VERSION 5.7 ;
  NOWIREEXTENSIONATPIN ON ;
  DIVIDERCHAR "/" ;
  BUSBITCHARS "[]" ;
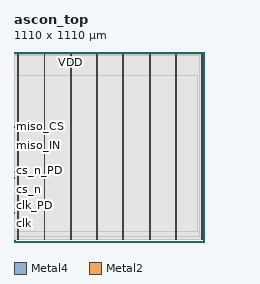
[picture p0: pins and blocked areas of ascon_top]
MACRO ascon_top
  CLASS BLOCK ;
  FOREIGN ascon_top ;
  ORIGIN 0.000 0.000 ;
  SIZE 1110.000 BY 1110.000 ;
  PIN VDD
    DIRECTION INOUT ;
    USE POWER ;
    PORT
      LAYER Metal4 ;
        RECT 22.240 15.380 23.840 1093.980 ;
    END
    PORT
      LAYER Metal4 ;
        RECT 175.840 15.380 177.440 1093.980 ;
    END
    PORT
      LAYER Metal4 ;
        RECT 329.440 15.380 331.040 1093.980 ;
    END
    PORT
      LAYER Metal4 ;
        RECT 483.040 15.380 484.640 1093.980 ;
    END
    PORT
      LAYER Metal4 ;
        RECT 636.640 15.380 638.240 1093.980 ;
    END
    PORT
      LAYER Metal4 ;
        RECT 790.240 15.380 791.840 1093.980 ;
    END
    PORT
      LAYER Metal4 ;
        RECT 943.840 15.380 945.440 1093.980 ;
    END
    PORT
      LAYER Metal4 ;
        RECT 1097.440 15.380 1099.040 1093.980 ;
    END
  END VDD
  PIN VSS
    DIRECTION INOUT ;
    USE GROUND ;
    PORT
      LAYER Metal4 ;
        RECT 25.540 15.380 27.140 1093.980 ;
    END
    PORT
      LAYER Metal4 ;
        RECT 179.140 15.380 180.740 1093.980 ;
    END
    PORT
      LAYER Metal4 ;
        RECT 332.740 15.380 334.340 1093.980 ;
    END
    PORT
      LAYER Metal4 ;
        RECT 486.340 15.380 487.940 1093.980 ;
    END
    PORT
      LAYER Metal4 ;
        RECT 639.940 15.380 641.540 1093.980 ;
    END
    PORT
      LAYER Metal4 ;
        RECT 793.540 15.380 795.140 1093.980 ;
    END
    PORT
      LAYER Metal4 ;
        RECT 947.140 15.380 948.740 1093.980 ;
    END
    PORT
      LAYER Metal4 ;
        RECT 1100.740 15.380 1102.340 1093.980 ;
    END
  END VSS
  PIN clk
    DIRECTION INPUT ;
    USE SIGNAL ;
    ANTENNAGATEAREA 4.738000 ;
    PORT
      LAYER Metal2 ;
        RECT 0.000 108.760 1.000 109.140 ;
    END
  END clk
  PIN clk_PD
    DIRECTION OUTPUT ;
    USE SIGNAL ;
    ANTENNADIFFAREA 0.360800 ;
    PORT
      LAYER Metal2 ;
        RECT 0.000 169.290 1.000 169.670 ;
    END
  END clk_PD
  PIN clk_PU
    DIRECTION OUTPUT ;
    USE SIGNAL ;
    ANTENNADIFFAREA 0.360800 ;
    PORT
      LAYER Metal2 ;
        RECT 0.000 173.655 1.000 174.035 ;
    END
  END clk_PU
  PIN cs_n
    DIRECTION INPUT ;
    USE SIGNAL ;
    ANTENNAGATEAREA 0.726000 ;
    PORT
      LAYER Metal2 ;
        RECT 0.000 308.760 1.000 309.140 ;
    END
  END cs_n
  PIN cs_n_PD
    DIRECTION OUTPUT ;
    USE SIGNAL ;
    ANTENNADIFFAREA 0.360800 ;
    PORT
      LAYER Metal2 ;
        RECT 0.000 369.290 1.000 369.670 ;
    END
  END cs_n_PD
  PIN cs_n_PU
    DIRECTION OUTPUT ;
    USE SIGNAL ;
    ANTENNADIFFAREA 0.360800 ;
    PORT
      LAYER Metal2 ;
        RECT 0.000 373.655 1.000 374.035 ;
    END
  END cs_n_PU
  PIN miso_CS
    DIRECTION OUTPUT ;
    USE SIGNAL ;
    ANTENNADIFFAREA 0.360800 ;
    PORT
      LAYER Metal2 ;
        RECT 0.000 676.260 1.000 676.640 ;
    END
  END miso_CS
  PIN miso_IE
    DIRECTION OUTPUT ;
    USE SIGNAL ;
    ANTENNADIFFAREA 0.360800 ;
    PORT
      LAYER Metal2 ;
        RECT 0.000 668.235 1.000 668.615 ;
    END
  END miso_IE
  PIN miso_IN
    DIRECTION INPUT ;
    USE SIGNAL ;
    ANTENNAGATEAREA 0.498500 ;
    PORT
      LAYER Metal2 ;
        RECT 0.000 608.760 1.000 609.140 ;
    END
  END miso_IN
  PIN miso_OE
    DIRECTION OUTPUT ;
    USE SIGNAL ;
    ANTENNADIFFAREA 0.536800 ;
    PORT
      LAYER Metal2 ;
        RECT 0.000 609.490 1.000 609.870 ;
    END
  END miso_OE
  PIN miso_OUT
    DIRECTION OUTPUT ;
    USE SIGNAL ;
    ANTENNADIFFAREA 1.986000 ;
    PORT
      LAYER Metal2 ;
        RECT 0.000 610.220 1.000 610.600 ;
    END
  END miso_OUT
  PIN miso_PD
    DIRECTION OUTPUT ;
    USE SIGNAL ;
    ANTENNADIFFAREA 0.360800 ;
    PORT
      LAYER Metal2 ;
        RECT 0.000 669.290 1.000 669.670 ;
    END
  END miso_PD
  PIN miso_PDRV0
    DIRECTION OUTPUT ;
    USE SIGNAL ;
    ANTENNADIFFAREA 0.536800 ;
    PORT
      LAYER Metal2 ;
        RECT 0.000 672.510 1.000 672.890 ;
    END
  END miso_PDRV0
  PIN miso_PDRV1
    DIRECTION OUTPUT ;
    USE SIGNAL ;
    ANTENNADIFFAREA 0.360800 ;
    PORT
      LAYER Metal2 ;
        RECT 0.000 671.800 1.000 672.180 ;
    END
  END miso_PDRV1
  PIN miso_PU
    DIRECTION OUTPUT ;
    USE SIGNAL ;
    ANTENNADIFFAREA 0.360800 ;
    PORT
      LAYER Metal2 ;
        RECT 0.000 673.655 1.000 674.035 ;
    END
  END miso_PU
  PIN miso_SL
    DIRECTION OUTPUT ;
    USE SIGNAL ;
    ANTENNADIFFAREA 0.360800 ;
    PORT
      LAYER Metal2 ;
        RECT 0.000 610.950 1.000 611.330 ;
    END
  END miso_SL
  PIN mosi
    DIRECTION INPUT ;
    USE SIGNAL ;
    ANTENNAGATEAREA 0.741000 ;
    PORT
      LAYER Metal2 ;
        RECT 0.000 508.760 1.000 509.140 ;
    END
  END mosi
  PIN mosi_PD
    DIRECTION OUTPUT ;
    USE SIGNAL ;
    ANTENNADIFFAREA 0.360800 ;
    PORT
      LAYER Metal2 ;
        RECT 0.000 569.290 1.000 569.670 ;
    END
  END mosi_PD
  PIN mosi_PU
    DIRECTION OUTPUT ;
    USE SIGNAL ;
    ANTENNADIFFAREA 0.360800 ;
    PORT
      LAYER Metal2 ;
        RECT 0.000 573.655 1.000 574.035 ;
    END
  END mosi_PU
  PIN rst
    DIRECTION INPUT ;
    USE SIGNAL ;
    ANTENNAGATEAREA 0.741000 ;
    PORT
      LAYER Metal2 ;
        RECT 0.000 208.760 1.000 209.140 ;
    END
  END rst
  PIN rst_PD
    DIRECTION OUTPUT ;
    USE SIGNAL ;
    ANTENNADIFFAREA 0.360800 ;
    PORT
      LAYER Metal2 ;
        RECT 0.000 269.290 1.000 269.670 ;
    END
  END rst_PD
  PIN rst_PU
    DIRECTION OUTPUT ;
    USE SIGNAL ;
    ANTENNADIFFAREA 0.360800 ;
    PORT
      LAYER Metal2 ;
        RECT 0.000 273.655 1.000 274.035 ;
    END
  END rst_PU
  PIN sclk
    DIRECTION INPUT ;
    USE SIGNAL ;
    ANTENNAGATEAREA 0.741000 ;
    PORT
      LAYER Metal2 ;
        RECT 0.000 408.760 1.000 409.140 ;
    END
  END sclk
  PIN sclk_PD
    DIRECTION OUTPUT ;
    USE SIGNAL ;
    ANTENNADIFFAREA 0.360800 ;
    PORT
      LAYER Metal2 ;
        RECT 0.000 469.290 1.000 469.670 ;
    END
  END sclk_PD
  PIN sclk_PU
    DIRECTION OUTPUT ;
    USE SIGNAL ;
    ANTENNADIFFAREA 0.360800 ;
    PORT
      LAYER Metal2 ;
        RECT 0.000 473.655 1.000 474.035 ;
    END
  END sclk_PU
  OBS
      LAYER Nwell ;
        RECT 6.290 15.250 1103.630 1094.110 ;
      LAYER Metal1 ;
        RECT 6.720 15.380 1103.200 1093.980 ;
      LAYER Metal2 ;
        RECT 0.140 676.940 1102.200 1093.870 ;
        RECT 1.300 675.960 1102.200 676.940 ;
        RECT 0.140 674.335 1102.200 675.960 ;
        RECT 1.300 673.355 1102.200 674.335 ;
        RECT 0.140 673.190 1102.200 673.355 ;
        RECT 1.300 671.500 1102.200 673.190 ;
        RECT 0.140 669.970 1102.200 671.500 ;
        RECT 1.300 668.990 1102.200 669.970 ;
        RECT 0.140 668.915 1102.200 668.990 ;
        RECT 1.300 667.935 1102.200 668.915 ;
        RECT 0.140 611.630 1102.200 667.935 ;
        RECT 1.300 608.460 1102.200 611.630 ;
        RECT 0.140 574.335 1102.200 608.460 ;
        RECT 1.300 573.355 1102.200 574.335 ;
        RECT 0.140 569.970 1102.200 573.355 ;
        RECT 1.300 568.990 1102.200 569.970 ;
        RECT 0.140 509.440 1102.200 568.990 ;
        RECT 1.300 508.460 1102.200 509.440 ;
        RECT 0.140 474.335 1102.200 508.460 ;
        RECT 1.300 473.355 1102.200 474.335 ;
        RECT 0.140 469.970 1102.200 473.355 ;
        RECT 1.300 468.990 1102.200 469.970 ;
        RECT 0.140 409.440 1102.200 468.990 ;
        RECT 1.300 408.460 1102.200 409.440 ;
        RECT 0.140 374.335 1102.200 408.460 ;
        RECT 1.300 373.355 1102.200 374.335 ;
        RECT 0.140 369.970 1102.200 373.355 ;
        RECT 1.300 368.990 1102.200 369.970 ;
        RECT 0.140 309.440 1102.200 368.990 ;
        RECT 1.300 308.460 1102.200 309.440 ;
        RECT 0.140 274.335 1102.200 308.460 ;
        RECT 1.300 273.355 1102.200 274.335 ;
        RECT 0.140 269.970 1102.200 273.355 ;
        RECT 1.300 268.990 1102.200 269.970 ;
        RECT 0.140 209.440 1102.200 268.990 ;
        RECT 1.300 208.460 1102.200 209.440 ;
        RECT 0.140 174.335 1102.200 208.460 ;
        RECT 1.300 173.355 1102.200 174.335 ;
        RECT 0.140 169.970 1102.200 173.355 ;
        RECT 1.300 168.990 1102.200 169.970 ;
        RECT 0.140 109.440 1102.200 168.990 ;
        RECT 1.300 108.460 1102.200 109.440 ;
        RECT 0.140 15.490 1102.200 108.460 ;
      LAYER Metal3 ;
        RECT 0.090 15.540 1102.250 1093.820 ;
      LAYER Metal4 ;
        RECT 0.140 29.770 21.940 1087.990 ;
        RECT 24.140 29.770 25.240 1087.990 ;
        RECT 27.440 29.770 175.540 1087.990 ;
        RECT 177.740 29.770 178.840 1087.990 ;
        RECT 181.040 29.770 329.140 1087.990 ;
        RECT 331.340 29.770 332.440 1087.990 ;
        RECT 334.640 29.770 482.740 1087.990 ;
        RECT 484.940 29.770 486.040 1087.990 ;
        RECT 488.240 29.770 636.340 1087.990 ;
        RECT 638.540 29.770 639.640 1087.990 ;
        RECT 641.840 29.770 789.940 1087.990 ;
        RECT 792.140 29.770 793.240 1087.990 ;
        RECT 795.440 29.770 943.540 1087.990 ;
        RECT 945.740 29.770 946.840 1087.990 ;
        RECT 949.040 29.770 1082.340 1087.990 ;
      LAYER Metal5 ;
        RECT 0.060 61.430 1073.460 973.570 ;
  END
END ascon_top
END LIBRARY

